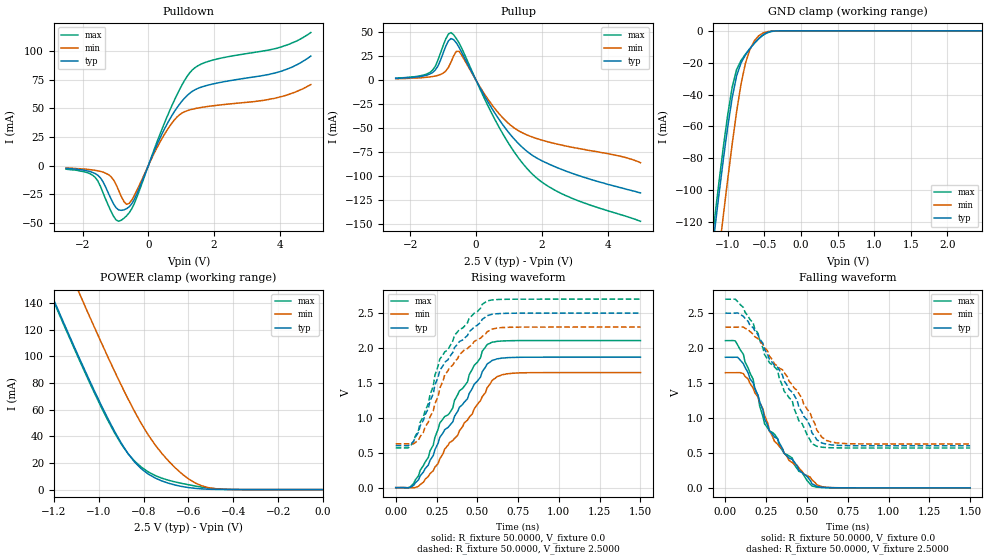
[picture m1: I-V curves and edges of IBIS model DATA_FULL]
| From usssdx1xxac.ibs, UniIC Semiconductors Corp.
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|   Model DATA_FULL
[Model]  DATA_FULL
Model_type   I/O
Polarity   Non-Inverting
Enable   Active-High
Vinl =   940.000mV
Vinh =   1.560V
Vmeas =   1.250V
Vref =   1.250V
Cref =   30.000pF
Rref =   50.000Ohm
C_comp   2.2640pF   2.2480pF   2.2810pF
[Temperature Range]   25.0000   70.0000   0.0
[Voltage Range]   2.5000V   2.3000V   2.7000V
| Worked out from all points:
|   slope of the pulldown table from 0 to 0.375 V, typ, clamps not added: 14.9 ohm
|   slope of the pullup table from 0 to 0.375 V, typ, clamps not added: 16.1 ohm
|   GND clamp passes 1 mA (typ) near -0.46 V on its own axis
|   POWER clamp passes 1 mA (typ) near -0.57 V on its own axis
|   rising waveform, R_fixture 50.0000, V_fixture 0.0: 20-80 % time 280ps typ, 282ps min, 271ps max; typ from 0 V to 1.87 V
|   rising waveform, R_fixture 50.0000, V_fixture 2.5000: 20-80 % time 240ps typ, 215ps min, 234ps max; typ from 0.602 V to 2.5 V
|   falling waveform, R_fixture 50.0000, V_fixture 0.0: 20-80 % time 251ps typ, 238ps min, 267ps max; typ from 1.87 V to 0 V
|   falling waveform, R_fixture 50.0000, V_fixture 2.5000: 20-80 % time 282ps typ, 283ps min, 263ps max; typ from 2.5 V to 0.602 V
[Pulldown]
|Voltage   I(typ)   I(min)   I(max)
-2.5V     -2.3mA     -2mA       -3mA
-1.62V    -6.8mA     -4mA       -10mA
-1.14V    -28.5mA    -9.4mA     -39.3mA
-980mV    -36.59mA   -16.4mA    -47.22mA
-820mV    -38.86mA   -26.86mA   -47.44mA
-580mV    -35.73mA   -32.78mA   -40.94mA
620mV     38.87mA    33.1mA     45.97mA
940mV     53.16mA    44.16mA    65.69mA
1.34V     64.79mA    49.2mA     83.42mA
1.98V     71.26mA    52.21mA    92.09mA
3.98V     81.7mA     59.7mA     102.9mA
4.94V     95.4mA     70.6mA     115.9mA
[Pullup]
|Voltage   I(typ)   I(min)   I(max)
-2.44V    1.9mA      1.6mA      2.2mA
-1.4V     6.5mA      3.4mA      8.1mA
-1.16V    14.5mA     5mA        20.7mA
-920mV    35.35mA    9.55mA     42.92mA
-760mV    43.44mA    18.82mA    49.71mA
-600mV    39.07mA    30.05mA    43.55mA
-520mV    34.55mA    30.19mA    39.18mA
680mV     -39.91mA   -34.13mA   -47.75mA
1.16V     -61.35mA   -49.83mA   -74.83mA
1.72V     -78.55mA   -59.42mA   -98.24mA
2.92V     -97.21mA   -70.01mA   -123.3mA
5V        -117.6mA   -86.1mA    -147.3mA
[GND_clamp]
|Voltage   I(typ)   I(min)   I(max)
-2.5V     -683.1mA   -721.3mA   -677.2mA
-1.24V    -149mA     -187mA     -141.5mA
-1.18V    -125.4mA   -162.7mA   -117.8mA
-1.12V    -102.4mA   -138.9mA   -94.64mA
-1.06V    -80.41mA   -115.5mA   -72.57mA
-940mV    -42.05mA   -71.05mA   -35.4mA
-880mV    -28.39mA   -50.93mA   -24.34mA
-760mV    -15.32mA   -20.58mA   -14.74mA
-700mV    -11.37mA   -12mA      -11.2mA
-520mV    -2.567mA   -1.422mA   -2.802mA
-280mV    -6.335uA   -9.119uA   -18.03uA
2.48V     19.82nA    197.4nA    8.434nA
[POWER_clamp]
|Voltage   I(typ)   I(min)   I(max)
-2.49V    671mA      720.4mA    671.3mA
-1.23V    154mA      203.6mA    152.8mA
-1.2V     142.3mA    191.8mA    141mA
-1.08V    96.37mA    145mA      94.93mA
-960mV    53.65mA    99.93mA    52.25mA
-870mV    27.22mA    68.36mA    27.16mA
-810mV    15.61mA    49.56mA    16.88mA
-750mV    8.845mA    33.93mA    10.7mA
-630mV    2.359mA    11.98mA    4.673mA
-570mV    942.1uA    4.996mA    2.692mA
-480mV    155.9uA    702.6uA    662.7uA
0V        21.05nA    13.45nA    12.78nA
[Ramp]
| variable   typ   min   max
dV/dt_r  1.1214/0.2791n   0.9888/0.2790n   1.2642/0.2705n
dV/dt_f  1.1387/0.2788n   1.0032/0.2797n   1.2781/0.2611n
R_load = 50.0000
[Rising Waveform]
R_fixture= 50.0000
V_fixture= 0.0
V_fixture_min= 0.0
V_fixture_max= 0.0
|time   V(typ)   V(min)   V(max)
0s        0V         0V         0V
90.91ps   6.734mV    -1.083mV   14.54mV
170ps     224.4mV    77.99mV    317.2mV
230ps     459mV      242mV      608.6mV
270ps     720.7mV    412.5mV    926.6mV
350ps     942.7mV    675.2mV    1.144V
560ps     1.771V     1.43V      2.049V
620ps     1.844V     1.589V     2.095V
710ps     1.864V     1.637V     2.105V
1.5ns     1.869V     1.648V     2.107V
[Rising Waveform]
R_fixture= 50.0000
V_fixture= 2.5000
V_fixture_min= 2.3000
V_fixture_max= 2.7000
|time   V(typ)   V(min)   V(max)
0s        602.1mV    628mV      569.9mV
90.91ps   618.5mV    626.3mV    596mV
140ps     795.1mV    684.1mV    824.8mV
230ps     1.345V     1.1V       1.453V
240ps     1.467V     1.2V       1.608V
270ps     1.679V     1.423V     1.84V
300ps     1.795V     1.613V     1.944V
390ps     2.092V     1.905V     2.266V
560ps     2.463V     2.232V     2.674V
1.5ns     2.5V       2.3V       2.7V
[Falling Waveform]
R_fixture= 50.0000
V_fixture= 0.0
V_fixture_min= 0.0
V_fixture_max= 0.0
|time   V(typ)   V(min)   V(max)
0s        1.869V     1.648V     2.107V
60.61ps   1.87V      1.648V     2.103V
140ps     1.644V     1.555V     1.71V
200ps     1.323V     1.3V       1.317V
240ps     988.9mV    1.035V     917mV
300ps     729.1mV    668.3mV    770.5mV
360ps     496.7mV    500.7mV    493.2mV
530ps     59.69mV    117mV      28.14mV
650ps     2.335mV    3.845mV    1.366mV
1.5ns     0V         0V         0V
[Falling Waveform]
R_fixture= 50.0000
V_fixture= 2.5000
V_fixture_min= 2.3000
V_fixture_max= 2.7000
|time   V(typ)   V(min)   V(max)
0s        2.5V       2.3V       2.7V
60.61ps   2.501V     2.299V     2.7V
170ps     2.291V     2.201V     2.362V
240ps     1.982V     2.009V     1.906V
320ps     1.725V     1.74V      1.684V
360ps     1.531V     1.651V     1.383V
530ps     790.5mV    999.2mV    633.4mV
590ps     643.1mV    726mV      581.8mV
680ps     609.2mV    643.6mV    572.2mV
1.5ns     602.1mV    628mV      569.9mV
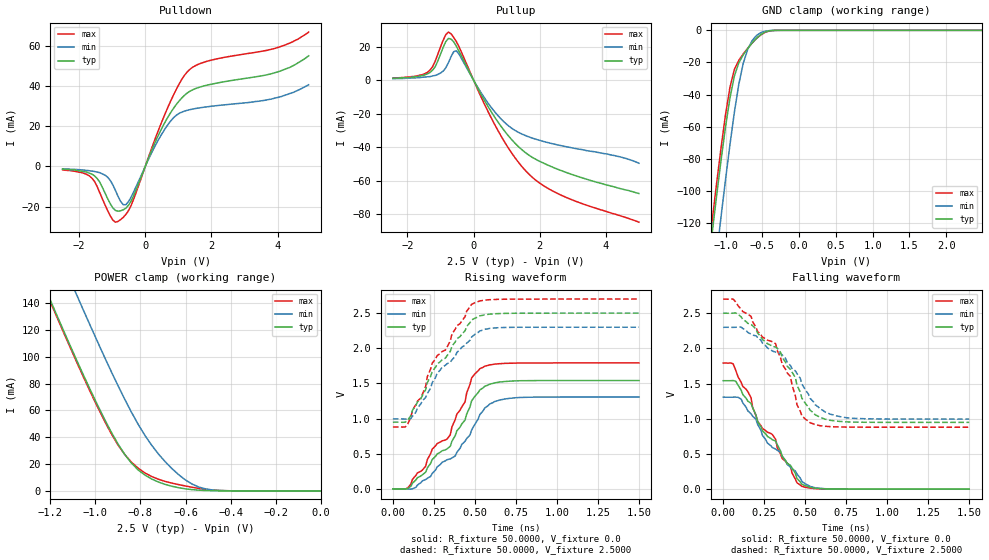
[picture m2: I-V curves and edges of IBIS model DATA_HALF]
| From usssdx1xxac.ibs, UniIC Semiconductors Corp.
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|   Model DATA_HALF
[Model]  DATA_HALF
Model_type   I/O
Polarity   Non-Inverting
Enable   Active-High
Vinl =   940.000mV
Vinh =   1.560V
Vmeas =   1.250V
Vref =   1.250V
Cref =   30.000pF
Rref =   50.000Ohm
C_comp   2.2640pF   2.2480pF   2.2810pF
[Temperature Range]   25.0000   70.0000   0.0
[Voltage Range]   2.5000V   2.3000V   2.7000V
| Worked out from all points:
|   slope of the pulldown table from 0 to 0.375 V, typ, clamps not added: 25.4 ohm
|   slope of the pullup table from 0 to 0.375 V, typ, clamps not added: 27.5 ohm
|   GND clamp passes 1 mA (typ) near -0.46 V on its own axis
|   POWER clamp passes 1 mA (typ) near -0.57 V on its own axis
|   rising waveform, R_fixture 50.0000, V_fixture 0.0: 20-80 % time 265ps typ, 271ps min, 257ps max; typ from 0 V to 1.54 V
|   rising waveform, R_fixture 50.0000, V_fixture 2.5000: 20-80 % time 256ps typ, 257ps min, 251ps max; typ from 0.949 V to 2.5 V
|   falling waveform, R_fixture 50.0000, V_fixture 0.0: 20-80 % time 257ps typ, 261ps min, 263ps max; typ from 1.54 V to 0 V
|   falling waveform, R_fixture 50.0000, V_fixture 2.5000: 20-80 % time 269ps typ, 286ps min, 256ps max; typ from 2.5 V to 0.949 V
[Pulldown]
|Voltage   I(typ)   I(min)   I(max)
-2.5V     -1.3mA     -1.2mA     -1.7mA
-1.62V    -3.8mA     -2.3mA     -5.7mA
-1.14V    -15.9mA    -5.3mA     -21.9mA
-820mV    -22.24mA   -14.96mA   -27.33mA
-660mV    -21.54mA   -19.11mA   -25.24mA
-500mV    -19.2mA    -17.34mA   -21.81mA
540mV     20.23mA    17.2mA     23.81mA
860mV     29.02mA    24.28mA    35.7mA
1.26V     36.38mA    27.86mA    46.85mA
1.9V      40.53mA    29.71mA    52.43mA
4.06V     47.3mA     34.5mA     59.4mA
4.94V     55mA       40.6mA     66.8mA
[Pullup]
|Voltage   I(typ)   I(min)   I(max)
-2.44V    1.1mA      900uA      1.2mA
-1.32V    4.5mA      2.1mA      5.9mA
-1.16V    8mA        2.8mA      11.3mA
-920mV    19.5mA     5.37mA     23.73mA
-760mV    24.84mA    10.39mA    28.62mA
-600mV    22.79mA    16.97mA    25.41mA
-520mV    20.23mA    17.49mA    22.95mA
680mV     -23.26mA   -19.81mA   -27.95mA
1.16V     -35.58mA   -28.74mA   -43.6mA
1.64V     -44.21mA   -33.54mA   -55.32mA
2.76V     -54.68mA   -39.47mA   -69.49mA
5V        -67.5mA    -49.5mA    -84.6mA
[GND_clamp]
|Voltage   I(typ)   I(min)   I(max)
-2.5V     -683.1mA   -721.3mA   -677.2mA
-1.24V    -149mA     -187mA     -141.5mA
-1.18V    -125.4mA   -162.7mA   -117.8mA
-1.12V    -102.4mA   -138.9mA   -94.64mA
-1.06V    -80.41mA   -115.5mA   -72.57mA
-940mV    -42.05mA   -71.05mA   -35.4mA
-880mV    -28.39mA   -50.93mA   -24.34mA
-760mV    -15.32mA   -20.58mA   -14.74mA
-700mV    -11.37mA   -12mA      -11.2mA
-520mV    -2.567mA   -1.422mA   -2.802mA
-280mV    -6.335uA   -9.119uA   -18.03uA
2.48V     19.82nA    197.4nA    8.434nA
[POWER_clamp]
|Voltage   I(typ)   I(min)   I(max)
-2.49V    671mA      720.4mA    671.3mA
-1.23V    154mA      203.6mA    152.8mA
-1.2V     142.3mA    191.8mA    141mA
-1.08V    96.37mA    145mA      94.93mA
-960mV    53.65mA    99.93mA    52.25mA
-870mV    27.22mA    68.36mA    27.16mA
-810mV    15.61mA    49.56mA    16.88mA
-750mV    8.845mA    33.93mA    10.7mA
-630mV    2.359mA    11.98mA    4.673mA
-570mV    942.1uA    4.996mA    2.692mA
-480mV    155.9uA    702.6uA    662.7uA
0V        21.05nA    13.45nA    12.78nA
[Ramp]
| variable   typ   min   max
dV/dt_r  0.9246/0.2643n   0.7842/0.2696n   1.0752/0.2577n
dV/dt_f  0.9306/0.2690n   0.7827/0.2817n   1.0918/0.2566n
R_load = 50.0000
[Rising Waveform]
R_fixture= 50.0000
V_fixture= 0.0
V_fixture_min= 0.0
V_fixture_max= 0.0
|time   V(typ)   V(min)   V(max)
0s        0V         0V         0V
90.91ps   5.845mV    -1.34mV    14.58mV
200ps     237.8mV    133.3mV    323.2mV
240ps     418.2mV    220.3mV    566mV
350ps     606mV      426.6mV    768.9mV
440ps     978.5mV    677.2mV    1.238V
480ps     1.251V     837.4mV    1.576V
560ps     1.459V     1.15V      1.745V
740ps     1.536V     1.295V     1.789V
1.5ns     1.541V     1.307V     1.792V
[Rising Waveform]
R_fixture= 50.0000
V_fixture= 2.5000
V_fixture_min= 2.3000
V_fixture_max= 2.7000
|time   V(typ)   V(min)   V(max)
0s        949mV      995.5mV    880.4mV
90.91ps   978.1mV    992.4mV    924.1mV
120ps     1.12V      1.034V     1.122V
200ps     1.411V     1.301V     1.461V
240ps     1.672V     1.512V     1.788V
320ps     1.859V     1.758V     1.974V
360ps     2.029V     1.835V     2.201V
480ps     2.402V     2.16V      2.624V
640ps     2.493V     2.292V     2.696V
1.5ns     2.5V       2.3V       2.7V
[Falling Waveform]
R_fixture= 50.0000
V_fixture= 0.0
V_fixture_min= 0.0
V_fixture_max= 0.0
|time   V(typ)   V(min)   V(max)
0s        1.541V     1.307V     1.792V
60.61ps   1.543V     1.307V     1.781V
110ps     1.406V     1.279V     1.517V
170ps     1.22V      1.071V     1.3V
210ps     961.6mV    921.5mV    962.8mV
300ps     701.4mV    590.5mV    776.7mV
360ps     465.4mV    470.7mV    435.7mV
480ps     70.89mV    109.4mV    39.43mV
620ps     4.617mV    6.487mV    2.541mV
1.5ns     -719.4nV   0V         0V
[Falling Waveform]
R_fixture= 50.0000
V_fixture= 2.5000
V_fixture_min= 2.3000
V_fixture_max= 2.7000
|time   V(typ)   V(min)   V(max)
0s        2.5V       2.3V       2.7V
110ps     2.448V     2.302V     2.557V
240ps     2.125V     2.074V     2.16V
320ps     2.019V     1.947V     2.067V
360ps     1.871V     1.907V     1.775V
410ps     1.702V     1.756V     1.602V
450ps     1.479V     1.642V     1.2V
530ps     1.121V     1.291V     943.6mV
740ps     957.2mV    1.019V     882.3mV
1.5ns     949mV      995.5mV    880.4mV
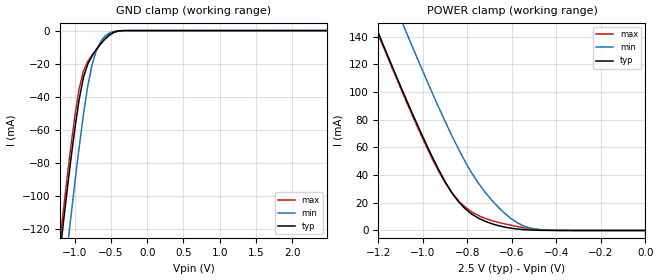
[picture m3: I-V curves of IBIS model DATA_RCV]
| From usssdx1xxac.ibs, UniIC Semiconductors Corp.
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|   Model DATA_RCV
[Model]  DATA_RCV
Model_type Input
Polarity   Non-Inverting
Vinl =   940.000mV
Vinh =   1.560V
C_comp   2.2640pF   2.2480pF   2.2810pF
[Temperature Range]   25.0000   70.0000   0.0
[Voltage Range]   2.5000V   2.3000V   2.7000V
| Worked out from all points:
|   GND clamp passes 1 mA (typ) near -0.46 V on its own axis
|   POWER clamp passes 1 mA (typ) near -0.57 V on its own axis
[GND_clamp]
|Voltage   I(typ)   I(min)   I(max)
-2.5V     -683.1mA   -721.3mA   -677.2mA
-1.24V    -149mA     -187mA     -141.5mA
-1.18V    -125.4mA   -162.7mA   -117.8mA
-1.12V    -102.4mA   -138.9mA   -94.64mA
-1.06V    -80.41mA   -115.5mA   -72.57mA
-940mV    -42.05mA   -71.05mA   -35.4mA
-880mV    -28.39mA   -50.93mA   -24.34mA
-760mV    -15.32mA   -20.58mA   -14.74mA
-700mV    -11.37mA   -12mA      -11.2mA
-520mV    -2.567mA   -1.422mA   -2.802mA
-280mV    -6.335uA   -9.119uA   -18.03uA
2.48V     19.82nA    197.4nA    8.434nA
[POWER_clamp]
|Voltage   I(typ)   I(min)   I(max)
-2.49V    671mA      720.4mA    671.3mA
-1.23V    154mA      203.6mA    152.8mA
-1.2V     142.3mA    191.8mA    141mA
-1.08V    96.37mA    145mA      94.93mA
-960mV    53.65mA    99.93mA    52.25mA
-870mV    27.22mA    68.36mA    27.16mA
-810mV    15.61mA    49.56mA    16.88mA
-750mV    8.845mA    33.93mA    10.7mA
-630mV    2.359mA    11.98mA    4.673mA
-570mV    942.1uA    4.996mA    2.692mA
-480mV    155.9uA    702.6uA    662.7uA
0V        21.05nA    13.45nA    12.78nA
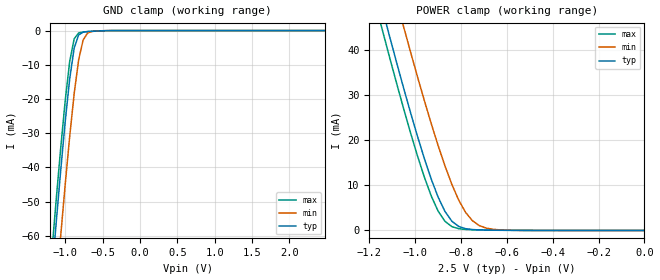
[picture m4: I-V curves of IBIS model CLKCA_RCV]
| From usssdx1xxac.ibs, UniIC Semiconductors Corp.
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|   Model CLKCA_RCV
[Model]  CLKCA_RCV
Model_type Input
Polarity   Non-Inverting
Vinl =   940.000mV
Vinh =   1.560V
C_comp   0.9200pF   0.8940pF   0.9290pF
[Temperature Range]   25.0000   70.0000   0.0
[Voltage Range]   2.5000V   2.3000V   2.7000V
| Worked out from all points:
|   GND clamp passes 1 mA (typ) near -0.80 V on its own axis
|   POWER clamp passes 1 mA (typ) near -0.81 V on its own axis
[GND_clamp]
|Voltage   I(typ)   I(min)   I(max)
-2.5V     -448.9mA   -467.1mA   -442.8mA
-1.18V    -71.75mA   -91.32mA   -65.01mA
-1.12V    -55.99mA   -75.42mA   -49.29mA
-1.06V    -40.81mA   -59.91mA   -34.26mA
-1V       -26.57mA   -44.98mA   -20.44mA
-940mV    -14.08mA   -30.94mA   -9.019mA
-880mV    -5.084mA   -18.39mA   -2.409mA
-820mV    -1.257mA   -8.498mA   -679uA
-760mV    -458.7uA   -2.729mA   -401uA
-700mV    -286.8uA   -719.9uA   -300.4uA
-640mV    -199.4uA   -240.4uA   -221.5uA
2.48V     17.21nA    6.962nA    2.488nA
[POWER_clamp]
|Voltage   I(typ)   I(min)   I(max)
-2.49V    329.6mA    342.4mA    325.4mA
-1.17V    54.42mA    68.25mA    49.76mA
-1.14V    48.58mA    62.39mA    43.92mA
-1.11V    42.81mA    56.59mA    38.17mA
-1.05V    31.57mA    45.19mA    27mA
-960mV    15.99mA    28.87mA    11.86mA
-900mV    7.429mA    18.88mA    4.306mA
-840mV    2.06mA     10.24mA    858.5uA
-780mV    395.6uA    4.018mA    227.3uA
-750mV    202.6uA    2.159mA    162.2uA
-630mV    43.47uA    130.3uA    72.77uA
0V        18.39nA    1.267nA    5.303nA
